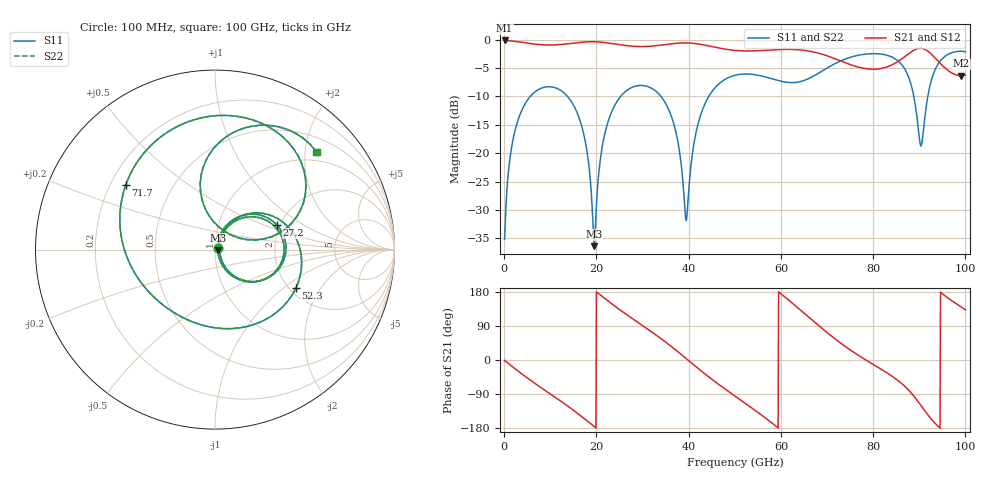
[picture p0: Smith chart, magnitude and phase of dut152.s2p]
! Touchstone file exported from HFSS 2026.1.0
!  File:  C:/ffzhzh/LocalFiles/Ansys_Project_Files/temp_test_TSV_RDL_152_1783464307_7600.aedt
!  Generated:  06:59:48 AM Jul  8, 2026
!  Design:  TSV_RDL
!  Project:  temp_test_TSV_RDL_152_1783464307_7600
! Variables:
!  h_bsmrdl = 3.67um
!  h_ox = 20um
!  h_rdl = 5um
!  h_sub = 96.24um
!  h_tmrdl = 2.21um
!  h_tsv = 96.24um
!  h_via = 3um
!  l_bsmrdl = 299.43um
!  l_sub = 2602.6um
!  l_tmrdl = 296.28um
!  m_sub = 200um
!  pitch = 46.18um
!  r_tsv = 13.5um
!  s_tmrdl = 10um
!  w_bsmrdl = 11.65um
!  w_sub = 500um
!  w_tmrdl = 28.08um
!  x_tsv_center1 = 310.32um
!  x_tsv_center2 = 621.4um
!  x_tsv_center3 = 945.76um
!  x_tsv_center4 = 1256.84um
!  x_tsv_center5 = 1581.2um
!  x_tsv_center6 = 1892.28um
# GHz S MA R 50.000000
! Terminal data exported
! Port[1] = TM_RDL1_1_T1
! Port[2] = TM_RDL5_1_T1
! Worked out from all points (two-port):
!   1000 points, 100 MHz to 100 GHz, reference 50 ohm
!   highest |S21| = -0.14 dB at 100 MHz (marker M1); lowest = -6.4 dB at 99.1 GHz (marker M2)
!   |S21| within 3 dB of the highest: start of sweep to 71.03 GHz; 86.6 GHz to 93.34 GHz (6.742 GHz wide, 7.49 % of centre)
!   lowest |S11| = -36.4 dB at 19.5 GHz (marker M3), VSWR 1.03, Z = 51.5 - j0.159 ohm
!   |S11| at or under -10 dB: start of sweep to 5.66 GHz; 13.74 GHz to 25.25 GHz (11.51 GHz wide, 59 % of centre); 34 GHz to 44.37 GHz (10.37 GHz wide, 26.5 % of centre) (the widest 3 of 4)
!   |S22| runs from -35.9 to -2.0 dB; largest |S21 - S12| = 3.2e-14
!   S11 on the Smith chart (normalised r, x): 100 MHz: 1.03, +0.02; 27.2 GHz: 1.92, +0.61; 52.3 GHz: 2.17, -1.23; 71.7 GHz: 0.26, +0.30; 100 GHz: 0.80, +2.24
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0.1  0.0175 25.7  0.9843 -1.0  0.9843 -1.0  0.0175 25.7
! Gamma 0 0 0 0
! Port Impedance 50 0 50 0
1.9  0.1305 62.1  0.9704 -18.6  0.9704 -18.6  0.1305 62.1
5.4  0.307 35.1  0.9282 -50.8  0.9282 -50.8  0.307 35.1
11.4  0.3731 -13.1  0.9015 -101.2  0.9015 -101.2  0.3731 -13.0
16.8  0.1741 -57.1  0.9495 -149.1  0.9495 -149.1  0.1741 -56.9
19.5  0.01521 -5.8  0.9586 -175.2  0.9586 -175.2  0.01599 -5.4
22.1  0.1648 62.8  0.9407 159.8  0.9407 159.8  0.1649 62.6
27.2  0.3711 21.7  0.8803 114.3  0.8803 114.3  0.3711 21.6
33.4  0.3369 -27.5  0.8898 61.9  0.8898 61.9  0.3368 -27.5
37.1  0.1619 -56.1  0.9284 27.4  0.9284 27.4  0.1618 -56.1
39.5  0.0256 7.0  0.9365 3.5  0.9365 3.5  0.02559 7.3
42.9  0.235 52.3  0.9045 -30.6  0.9045 -30.6  0.2351 52.3
50.1  0.4864 -7.2  0.8043 -95.5  0.8043 -95.5  0.4863 -7.1
52.3  0.4989 -25.3  0.7957 -114.3  0.7957 -114.3  0.4988 -25.2
59.9  0.432 -93.7  0.8195 175.9  0.8195 175.9  0.4319 -93.6
66.7  0.4689 -165.2  0.7854 106.3  0.7854 106.3  0.4689 -165.2
71.7  0.6145 144.0  0.6805 56.1  0.6805 56.1  0.6147 143.8
83.4  0.7207 54.8  0.5839 -37.0  0.5839 -37.0  0.7209 54.6
90.4  0.1157 60.9  0.839 -120.5  0.839 -120.5  0.1141 61.0
93.5  0.5517 91.8  0.6859 -167.9  0.6859 -167.9  0.552 91.8
99.1  0.7909 49.7  0.481 139.9  0.481 139.9  0.7915 49.6
100  0.7828 43.8  0.487 132.4  0.487 132.4  0.7834 43.8
